VERSION 5.7 ;
  NOWIREEXTENSIONATPIN ON ;
  DIVIDERCHAR "/" ;
  BUSBITCHARS "[]" ;
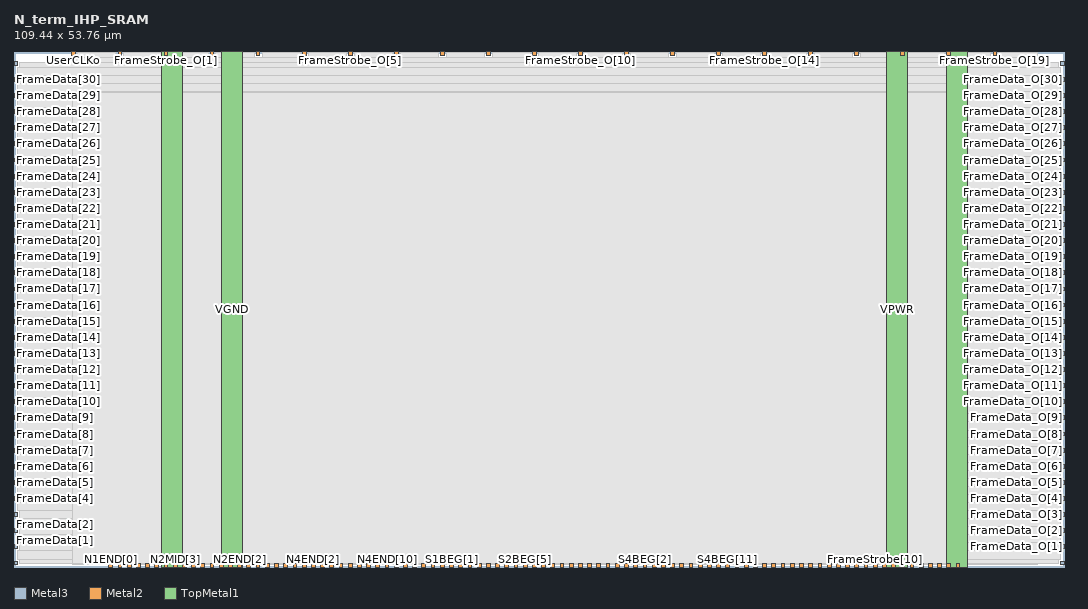
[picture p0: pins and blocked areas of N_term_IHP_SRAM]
MACRO N_term_IHP_SRAM
  CLASS BLOCK ;
  FOREIGN N_term_IHP_SRAM ;
  ORIGIN 0.000 0.000 ;
  SIZE 109.440 BY 53.760 ;
  PIN FrameData[0]
    DIRECTION INPUT ;
    USE SIGNAL ;
    ANTENNAGATEAREA 0.180700 ;
    PORT
      LAYER Metal3 ;
        RECT 0.000 0.220 0.400 0.620 ;
    END
  END FrameData[0]
  PIN FrameData[10]
    DIRECTION INPUT ;
    USE SIGNAL ;
    ANTENNAGATEAREA 0.180700 ;
    PORT
      LAYER Metal3 ;
        RECT 0.000 17.020 0.400 17.420 ;
    END
  END FrameData[10]
  PIN FrameData[11]
    DIRECTION INPUT ;
    USE SIGNAL ;
    ANTENNAGATEAREA 0.180700 ;
    PORT
      LAYER Metal3 ;
        RECT 0.000 18.700 0.400 19.100 ;
    END
  END FrameData[11]
  PIN FrameData[12]
    DIRECTION INPUT ;
    USE SIGNAL ;
    ANTENNAGATEAREA 0.180700 ;
    PORT
      LAYER Metal3 ;
        RECT 0.000 20.380 0.400 20.780 ;
    END
  END FrameData[12]
  PIN FrameData[13]
    DIRECTION INPUT ;
    USE SIGNAL ;
    ANTENNAGATEAREA 0.180700 ;
    PORT
      LAYER Metal3 ;
        RECT 0.000 22.060 0.400 22.460 ;
    END
  END FrameData[13]
  PIN FrameData[14]
    DIRECTION INPUT ;
    USE SIGNAL ;
    ANTENNAGATEAREA 0.180700 ;
    PORT
      LAYER Metal3 ;
        RECT 0.000 23.740 0.400 24.140 ;
    END
  END FrameData[14]
  PIN FrameData[15]
    DIRECTION INPUT ;
    USE SIGNAL ;
    ANTENNAGATEAREA 0.180700 ;
    PORT
      LAYER Metal3 ;
        RECT 0.000 25.420 0.400 25.820 ;
    END
  END FrameData[15]
  PIN FrameData[16]
    DIRECTION INPUT ;
    USE SIGNAL ;
    ANTENNAGATEAREA 0.180700 ;
    PORT
      LAYER Metal3 ;
        RECT 0.000 27.100 0.400 27.500 ;
    END
  END FrameData[16]
  PIN FrameData[17]
    DIRECTION INPUT ;
    USE SIGNAL ;
    ANTENNAGATEAREA 0.180700 ;
    PORT
      LAYER Metal3 ;
        RECT 0.000 28.780 0.400 29.180 ;
    END
  END FrameData[17]
  PIN FrameData[18]
    DIRECTION INPUT ;
    USE SIGNAL ;
    ANTENNAGATEAREA 0.180700 ;
    PORT
      LAYER Metal3 ;
        RECT 0.000 30.460 0.400 30.860 ;
    END
  END FrameData[18]
  PIN FrameData[19]
    DIRECTION INPUT ;
    USE SIGNAL ;
    ANTENNAGATEAREA 0.180700 ;
    PORT
      LAYER Metal3 ;
        RECT 0.000 32.140 0.400 32.540 ;
    END
  END FrameData[19]
  PIN FrameData[1]
    DIRECTION INPUT ;
    USE SIGNAL ;
    ANTENNAGATEAREA 0.180700 ;
    PORT
      LAYER Metal3 ;
        RECT 0.000 1.900 0.400 2.300 ;
    END
  END FrameData[1]
  PIN FrameData[20]
    DIRECTION INPUT ;
    USE SIGNAL ;
    ANTENNAGATEAREA 0.180700 ;
    PORT
      LAYER Metal3 ;
        RECT 0.000 33.820 0.400 34.220 ;
    END
  END FrameData[20]
  PIN FrameData[21]
    DIRECTION INPUT ;
    USE SIGNAL ;
    ANTENNAGATEAREA 0.180700 ;
    PORT
      LAYER Metal3 ;
        RECT 0.000 35.500 0.400 35.900 ;
    END
  END FrameData[21]
  PIN FrameData[22]
    DIRECTION INPUT ;
    USE SIGNAL ;
    ANTENNAGATEAREA 0.180700 ;
    PORT
      LAYER Metal3 ;
        RECT 0.000 37.180 0.400 37.580 ;
    END
  END FrameData[22]
  PIN FrameData[23]
    DIRECTION INPUT ;
    USE SIGNAL ;
    ANTENNAGATEAREA 0.180700 ;
    PORT
      LAYER Metal3 ;
        RECT 0.000 38.860 0.400 39.260 ;
    END
  END FrameData[23]
  PIN FrameData[24]
    DIRECTION INPUT ;
    USE SIGNAL ;
    ANTENNAGATEAREA 0.180700 ;
    PORT
      LAYER Metal3 ;
        RECT 0.000 40.540 0.400 40.940 ;
    END
  END FrameData[24]
  PIN FrameData[25]
    DIRECTION INPUT ;
    USE SIGNAL ;
    ANTENNAGATEAREA 0.180700 ;
    PORT
      LAYER Metal3 ;
        RECT 0.000 42.220 0.400 42.620 ;
    END
  END FrameData[25]
  PIN FrameData[26]
    DIRECTION INPUT ;
    USE SIGNAL ;
    ANTENNAGATEAREA 0.180700 ;
    PORT
      LAYER Metal3 ;
        RECT 0.000 43.900 0.400 44.300 ;
    END
  END FrameData[26]
  PIN FrameData[27]
    DIRECTION INPUT ;
    USE SIGNAL ;
    ANTENNAGATEAREA 0.180700 ;
    PORT
      LAYER Metal3 ;
        RECT 0.000 45.580 0.400 45.980 ;
    END
  END FrameData[27]
  PIN FrameData[28]
    DIRECTION INPUT ;
    USE SIGNAL ;
    ANTENNAGATEAREA 0.180700 ;
    PORT
      LAYER Metal3 ;
        RECT 0.000 47.260 0.400 47.660 ;
    END
  END FrameData[28]
  PIN FrameData[29]
    DIRECTION INPUT ;
    USE SIGNAL ;
    ANTENNAGATEAREA 0.180700 ;
    PORT
      LAYER Metal3 ;
        RECT 0.000 48.940 0.400 49.340 ;
    END
  END FrameData[29]
  PIN FrameData[2]
    DIRECTION INPUT ;
    USE SIGNAL ;
    ANTENNAGATEAREA 0.180700 ;
    PORT
      LAYER Metal3 ;
        RECT 0.000 3.580 0.400 3.980 ;
    END
  END FrameData[2]
  PIN FrameData[30]
    DIRECTION INPUT ;
    USE SIGNAL ;
    ANTENNAGATEAREA 0.180700 ;
    PORT
      LAYER Metal3 ;
        RECT 0.000 50.620 0.400 51.020 ;
    END
  END FrameData[30]
  PIN FrameData[31]
    DIRECTION INPUT ;
    USE SIGNAL ;
    ANTENNAGATEAREA 0.180700 ;
    PORT
      LAYER Metal3 ;
        RECT 0.000 52.300 0.400 52.700 ;
    END
  END FrameData[31]
  PIN FrameData[3]
    DIRECTION INPUT ;
    USE SIGNAL ;
    ANTENNAGATEAREA 0.180700 ;
    PORT
      LAYER Metal3 ;
        RECT 0.000 5.260 0.400 5.660 ;
    END
  END FrameData[3]
  PIN FrameData[4]
    DIRECTION INPUT ;
    USE SIGNAL ;
    ANTENNAGATEAREA 0.180700 ;
    PORT
      LAYER Metal3 ;
        RECT 0.000 6.940 0.400 7.340 ;
    END
  END FrameData[4]
  PIN FrameData[5]
    DIRECTION INPUT ;
    USE SIGNAL ;
    ANTENNAGATEAREA 0.180700 ;
    PORT
      LAYER Metal3 ;
        RECT 0.000 8.620 0.400 9.020 ;
    END
  END FrameData[5]
  PIN FrameData[6]
    DIRECTION INPUT ;
    USE SIGNAL ;
    ANTENNAGATEAREA 0.180700 ;
    PORT
      LAYER Metal3 ;
        RECT 0.000 10.300 0.400 10.700 ;
    END
  END FrameData[6]
  PIN FrameData[7]
    DIRECTION INPUT ;
    USE SIGNAL ;
    ANTENNAGATEAREA 0.180700 ;
    PORT
      LAYER Metal3 ;
        RECT 0.000 11.980 0.400 12.380 ;
    END
  END FrameData[7]
  PIN FrameData[8]
    DIRECTION INPUT ;
    USE SIGNAL ;
    ANTENNAGATEAREA 0.180700 ;
    PORT
      LAYER Metal3 ;
        RECT 0.000 13.660 0.400 14.060 ;
    END
  END FrameData[8]
  PIN FrameData[9]
    DIRECTION INPUT ;
    USE SIGNAL ;
    ANTENNAGATEAREA 0.180700 ;
    PORT
      LAYER Metal3 ;
        RECT 0.000 15.340 0.400 15.740 ;
    END
  END FrameData[9]
  PIN FrameData_O[0]
    DIRECTION OUTPUT ;
    USE SIGNAL ;
    ANTENNADIFFAREA 0.708600 ;
    PORT
      LAYER Metal3 ;
        RECT 109.040 0.220 109.440 0.620 ;
    END
  END FrameData_O[0]
  PIN FrameData_O[10]
    DIRECTION OUTPUT ;
    USE SIGNAL ;
    ANTENNADIFFAREA 0.708600 ;
    PORT
      LAYER Metal3 ;
        RECT 109.040 17.020 109.440 17.420 ;
    END
  END FrameData_O[10]
  PIN FrameData_O[11]
    DIRECTION OUTPUT ;
    USE SIGNAL ;
    ANTENNADIFFAREA 0.708600 ;
    PORT
      LAYER Metal3 ;
        RECT 109.040 18.700 109.440 19.100 ;
    END
  END FrameData_O[11]
  PIN FrameData_O[12]
    DIRECTION OUTPUT ;
    USE SIGNAL ;
    ANTENNADIFFAREA 0.708600 ;
    PORT
      LAYER Metal3 ;
        RECT 109.040 20.380 109.440 20.780 ;
    END
  END FrameData_O[12]
  PIN FrameData_O[13]
    DIRECTION OUTPUT ;
    USE SIGNAL ;
    ANTENNADIFFAREA 0.708600 ;
    PORT
      LAYER Metal3 ;
        RECT 109.040 22.060 109.440 22.460 ;
    END
  END FrameData_O[13]
  PIN FrameData_O[14]
    DIRECTION OUTPUT ;
    USE SIGNAL ;
    ANTENNADIFFAREA 0.708600 ;
    PORT
      LAYER Metal3 ;
        RECT 109.040 23.740 109.440 24.140 ;
    END
  END FrameData_O[14]
  PIN FrameData_O[15]
    DIRECTION OUTPUT ;
    USE SIGNAL ;
    ANTENNADIFFAREA 0.708600 ;
    PORT
      LAYER Metal3 ;
        RECT 109.040 25.420 109.440 25.820 ;
    END
  END FrameData_O[15]
  PIN FrameData_O[16]
    DIRECTION OUTPUT ;
    USE SIGNAL ;
    ANTENNADIFFAREA 0.708600 ;
    PORT
      LAYER Metal3 ;
        RECT 109.040 27.100 109.440 27.500 ;
    END
  END FrameData_O[16]
  PIN FrameData_O[17]
    DIRECTION OUTPUT ;
    USE SIGNAL ;
    ANTENNADIFFAREA 0.708600 ;
    PORT
      LAYER Metal3 ;
        RECT 109.040 28.780 109.440 29.180 ;
    END
  END FrameData_O[17]
  PIN FrameData_O[18]
    DIRECTION OUTPUT ;
    USE SIGNAL ;
    ANTENNADIFFAREA 0.708600 ;
    PORT
      LAYER Metal3 ;
        RECT 109.040 30.460 109.440 30.860 ;
    END
  END FrameData_O[18]
  PIN FrameData_O[19]
    DIRECTION OUTPUT ;
    USE SIGNAL ;
    ANTENNADIFFAREA 0.708600 ;
    PORT
      LAYER Metal3 ;
        RECT 109.040 32.140 109.440 32.540 ;
    END
  END FrameData_O[19]
  PIN FrameData_O[1]
    DIRECTION OUTPUT ;
    USE SIGNAL ;
    ANTENNADIFFAREA 0.708600 ;
    PORT
      LAYER Metal3 ;
        RECT 109.040 1.900 109.440 2.300 ;
    END
  END FrameData_O[1]
  PIN FrameData_O[20]
    DIRECTION OUTPUT ;
    USE SIGNAL ;
    ANTENNADIFFAREA 0.708600 ;
    PORT
      LAYER Metal3 ;
        RECT 109.040 33.820 109.440 34.220 ;
    END
  END FrameData_O[20]
  PIN FrameData_O[21]
    DIRECTION OUTPUT ;
    USE SIGNAL ;
    ANTENNADIFFAREA 0.708600 ;
    PORT
      LAYER Metal3 ;
        RECT 109.040 35.500 109.440 35.900 ;
    END
  END FrameData_O[21]
  PIN FrameData_O[22]
    DIRECTION OUTPUT ;
    USE SIGNAL ;
    ANTENNADIFFAREA 0.708600 ;
    PORT
      LAYER Metal3 ;
        RECT 109.040 37.180 109.440 37.580 ;
    END
  END FrameData_O[22]
  PIN FrameData_O[23]
    DIRECTION OUTPUT ;
    USE SIGNAL ;
    ANTENNADIFFAREA 0.708600 ;
    PORT
      LAYER Metal3 ;
        RECT 109.040 38.860 109.440 39.260 ;
    END
  END FrameData_O[23]
  PIN FrameData_O[24]
    DIRECTION OUTPUT ;
    USE SIGNAL ;
    ANTENNADIFFAREA 0.708600 ;
    PORT
      LAYER Metal3 ;
        RECT 109.040 40.540 109.440 40.940 ;
    END
  END FrameData_O[24]
  PIN FrameData_O[25]
    DIRECTION OUTPUT ;
    USE SIGNAL ;
    ANTENNADIFFAREA 0.708600 ;
    PORT
      LAYER Metal3 ;
        RECT 109.040 42.220 109.440 42.620 ;
    END
  END FrameData_O[25]
  PIN FrameData_O[26]
    DIRECTION OUTPUT ;
    USE SIGNAL ;
    ANTENNADIFFAREA 0.708600 ;
    PORT
      LAYER Metal3 ;
        RECT 109.040 43.900 109.440 44.300 ;
    END
  END FrameData_O[26]
  PIN FrameData_O[27]
    DIRECTION OUTPUT ;
    USE SIGNAL ;
    ANTENNADIFFAREA 0.708600 ;
    PORT
      LAYER Metal3 ;
        RECT 109.040 45.580 109.440 45.980 ;
    END
  END FrameData_O[27]
  PIN FrameData_O[28]
    DIRECTION OUTPUT ;
    USE SIGNAL ;
    ANTENNADIFFAREA 0.708600 ;
    PORT
      LAYER Metal3 ;
        RECT 109.040 47.260 109.440 47.660 ;
    END
  END FrameData_O[28]
  PIN FrameData_O[29]
    DIRECTION OUTPUT ;
    USE SIGNAL ;
    ANTENNADIFFAREA 0.708600 ;
    PORT
      LAYER Metal3 ;
        RECT 109.040 48.940 109.440 49.340 ;
    END
  END FrameData_O[29]
  PIN FrameData_O[2]
    DIRECTION OUTPUT ;
    USE SIGNAL ;
    ANTENNADIFFAREA 0.708600 ;
    PORT
      LAYER Metal3 ;
        RECT 109.040 3.580 109.440 3.980 ;
    END
  END FrameData_O[2]
  PIN FrameData_O[30]
    DIRECTION OUTPUT ;
    USE SIGNAL ;
    ANTENNADIFFAREA 0.708600 ;
    PORT
      LAYER Metal3 ;
        RECT 109.040 50.620 109.440 51.020 ;
    END
  END FrameData_O[30]
  PIN FrameData_O[31]
    DIRECTION OUTPUT ;
    USE SIGNAL ;
    ANTENNADIFFAREA 0.708600 ;
    PORT
      LAYER Metal3 ;
        RECT 109.040 52.300 109.440 52.700 ;
    END
  END FrameData_O[31]
  PIN FrameData_O[3]
    DIRECTION OUTPUT ;
    USE SIGNAL ;
    ANTENNADIFFAREA 0.708600 ;
    PORT
      LAYER Metal3 ;
        RECT 109.040 5.260 109.440 5.660 ;
    END
  END FrameData_O[3]
  PIN FrameData_O[4]
    DIRECTION OUTPUT ;
    USE SIGNAL ;
    ANTENNADIFFAREA 0.708600 ;
    PORT
      LAYER Metal3 ;
        RECT 109.040 6.940 109.440 7.340 ;
    END
  END FrameData_O[4]
  PIN FrameData_O[5]
    DIRECTION OUTPUT ;
    USE SIGNAL ;
    ANTENNADIFFAREA 0.708600 ;
    PORT
      LAYER Metal3 ;
        RECT 109.040 8.620 109.440 9.020 ;
    END
  END FrameData_O[5]
  PIN FrameData_O[6]
    DIRECTION OUTPUT ;
    USE SIGNAL ;
    ANTENNADIFFAREA 0.708600 ;
    PORT
      LAYER Metal3 ;
        RECT 109.040 10.300 109.440 10.700 ;
    END
  END FrameData_O[6]
  PIN FrameData_O[7]
    DIRECTION OUTPUT ;
    USE SIGNAL ;
    ANTENNADIFFAREA 0.708600 ;
    PORT
      LAYER Metal3 ;
        RECT 109.040 11.980 109.440 12.380 ;
    END
  END FrameData_O[7]
  PIN FrameData_O[8]
    DIRECTION OUTPUT ;
    USE SIGNAL ;
    ANTENNADIFFAREA 0.708600 ;
    PORT
      LAYER Metal3 ;
        RECT 109.040 13.660 109.440 14.060 ;
    END
  END FrameData_O[8]
  PIN FrameData_O[9]
    DIRECTION OUTPUT ;
    USE SIGNAL ;
    ANTENNADIFFAREA 0.708600 ;
    PORT
      LAYER Metal3 ;
        RECT 109.040 15.340 109.440 15.740 ;
    END
  END FrameData_O[9]
  PIN FrameStrobe[0]
    DIRECTION INPUT ;
    USE SIGNAL ;
    ANTENNAGATEAREA 0.180700 ;
    PORT
      LAYER Metal2 ;
        RECT 79.960 0.000 80.360 0.400 ;
    END
  END FrameStrobe[0]
  PIN FrameStrobe[10]
    DIRECTION INPUT ;
    USE SIGNAL ;
    ANTENNAGATEAREA 0.180700 ;
    PORT
      LAYER Metal2 ;
        RECT 89.560 0.000 89.960 0.400 ;
    END
  END FrameStrobe[10]
  PIN FrameStrobe[11]
    DIRECTION INPUT ;
    USE SIGNAL ;
    ANTENNAGATEAREA 0.180700 ;
    PORT
      LAYER Metal2 ;
        RECT 90.520 0.000 90.920 0.400 ;
    END
  END FrameStrobe[11]
  PIN FrameStrobe[12]
    DIRECTION INPUT ;
    USE SIGNAL ;
    ANTENNAGATEAREA 0.180700 ;
    PORT
      LAYER Metal2 ;
        RECT 91.480 0.000 91.880 0.400 ;
    END
  END FrameStrobe[12]
  PIN FrameStrobe[13]
    DIRECTION INPUT ;
    USE SIGNAL ;
    ANTENNAGATEAREA 0.180700 ;
    PORT
      LAYER Metal2 ;
        RECT 92.440 0.000 92.840 0.400 ;
    END
  END FrameStrobe[13]
  PIN FrameStrobe[14]
    DIRECTION INPUT ;
    USE SIGNAL ;
    ANTENNAGATEAREA 0.180700 ;
    PORT
      LAYER Metal2 ;
        RECT 93.400 0.000 93.800 0.400 ;
    END
  END FrameStrobe[14]
  PIN FrameStrobe[15]
    DIRECTION INPUT ;
    USE SIGNAL ;
    ANTENNAGATEAREA 0.180700 ;
    PORT
      LAYER Metal2 ;
        RECT 94.360 0.000 94.760 0.400 ;
    END
  END FrameStrobe[15]
  PIN FrameStrobe[16]
    DIRECTION INPUT ;
    USE SIGNAL ;
    ANTENNAGATEAREA 0.180700 ;
    PORT
      LAYER Metal2 ;
        RECT 95.320 0.000 95.720 0.400 ;
    END
  END FrameStrobe[16]
  PIN FrameStrobe[17]
    DIRECTION INPUT ;
    USE SIGNAL ;
    ANTENNAGATEAREA 0.180700 ;
    PORT
      LAYER Metal2 ;
        RECT 96.280 0.000 96.680 0.400 ;
    END
  END FrameStrobe[17]
  PIN FrameStrobe[18]
    DIRECTION INPUT ;
    USE SIGNAL ;
    ANTENNAGATEAREA 0.180700 ;
    PORT
      LAYER Metal2 ;
        RECT 97.240 0.000 97.640 0.400 ;
    END
  END FrameStrobe[18]
  PIN FrameStrobe[19]
    DIRECTION INPUT ;
    USE SIGNAL ;
    ANTENNAGATEAREA 0.180700 ;
    PORT
      LAYER Metal2 ;
        RECT 98.200 0.000 98.600 0.400 ;
    END
  END FrameStrobe[19]
  PIN FrameStrobe[1]
    DIRECTION INPUT ;
    USE SIGNAL ;
    ANTENNAGATEAREA 0.180700 ;
    PORT
      LAYER Metal2 ;
        RECT 80.920 0.000 81.320 0.400 ;
    END
  END FrameStrobe[1]
  PIN FrameStrobe[2]
    DIRECTION INPUT ;
    USE SIGNAL ;
    ANTENNAGATEAREA 0.180700 ;
    PORT
      LAYER Metal2 ;
        RECT 81.880 0.000 82.280 0.400 ;
    END
  END FrameStrobe[2]
  PIN FrameStrobe[3]
    DIRECTION INPUT ;
    USE SIGNAL ;
    ANTENNAGATEAREA 0.180700 ;
    PORT
      LAYER Metal2 ;
        RECT 82.840 0.000 83.240 0.400 ;
    END
  END FrameStrobe[3]
  PIN FrameStrobe[4]
    DIRECTION INPUT ;
    USE SIGNAL ;
    ANTENNAGATEAREA 0.180700 ;
    PORT
      LAYER Metal2 ;
        RECT 83.800 0.000 84.200 0.400 ;
    END
  END FrameStrobe[4]
  PIN FrameStrobe[5]
    DIRECTION INPUT ;
    USE SIGNAL ;
    ANTENNAGATEAREA 0.180700 ;
    PORT
      LAYER Metal2 ;
        RECT 84.760 0.000 85.160 0.400 ;
    END
  END FrameStrobe[5]
  PIN FrameStrobe[6]
    DIRECTION INPUT ;
    USE SIGNAL ;
    ANTENNAGATEAREA 0.180700 ;
    PORT
      LAYER Metal2 ;
        RECT 85.720 0.000 86.120 0.400 ;
    END
  END FrameStrobe[6]
  PIN FrameStrobe[7]
    DIRECTION INPUT ;
    USE SIGNAL ;
    ANTENNAGATEAREA 0.180700 ;
    PORT
      LAYER Metal2 ;
        RECT 86.680 0.000 87.080 0.400 ;
    END
  END FrameStrobe[7]
  PIN FrameStrobe[8]
    DIRECTION INPUT ;
    USE SIGNAL ;
    ANTENNAGATEAREA 0.180700 ;
    PORT
      LAYER Metal2 ;
        RECT 87.640 0.000 88.040 0.400 ;
    END
  END FrameStrobe[8]
  PIN FrameStrobe[9]
    DIRECTION INPUT ;
    USE SIGNAL ;
    ANTENNAGATEAREA 0.180700 ;
    PORT
      LAYER Metal2 ;
        RECT 88.600 0.000 89.000 0.400 ;
    END
  END FrameStrobe[9]
  PIN FrameStrobe_O[0]
    DIRECTION OUTPUT ;
    USE SIGNAL ;
    ANTENNADIFFAREA 0.708600 ;
    PORT
      LAYER Metal2 ;
        RECT 10.840 53.360 11.240 53.760 ;
    END
  END FrameStrobe_O[0]
  PIN FrameStrobe_O[10]
    DIRECTION OUTPUT ;
    USE SIGNAL ;
    ANTENNADIFFAREA 0.708600 ;
    PORT
      LAYER Metal2 ;
        RECT 58.840 53.360 59.240 53.760 ;
    END
  END FrameStrobe_O[10]
  PIN FrameStrobe_O[11]
    DIRECTION OUTPUT ;
    USE SIGNAL ;
    ANTENNADIFFAREA 0.708600 ;
    PORT
      LAYER Metal2 ;
        RECT 63.640 53.360 64.040 53.760 ;
    END
  END FrameStrobe_O[11]
  PIN FrameStrobe_O[12]
    DIRECTION OUTPUT ;
    USE SIGNAL ;
    ANTENNADIFFAREA 0.708600 ;
    PORT
      LAYER Metal2 ;
        RECT 68.440 53.360 68.840 53.760 ;
    END
  END FrameStrobe_O[12]
  PIN FrameStrobe_O[13]
    DIRECTION OUTPUT ;
    USE SIGNAL ;
    ANTENNADIFFAREA 0.708600 ;
    PORT
      LAYER Metal2 ;
        RECT 73.240 53.360 73.640 53.760 ;
    END
  END FrameStrobe_O[13]
  PIN FrameStrobe_O[14]
    DIRECTION OUTPUT ;
    USE SIGNAL ;
    ANTENNADIFFAREA 0.708600 ;
    PORT
      LAYER Metal2 ;
        RECT 78.040 53.360 78.440 53.760 ;
    END
  END FrameStrobe_O[14]
  PIN FrameStrobe_O[15]
    DIRECTION OUTPUT ;
    USE SIGNAL ;
    ANTENNADIFFAREA 0.708600 ;
    PORT
      LAYER Metal2 ;
        RECT 82.840 53.360 83.240 53.760 ;
    END
  END FrameStrobe_O[15]
  PIN FrameStrobe_O[16]
    DIRECTION OUTPUT ;
    USE SIGNAL ;
    ANTENNADIFFAREA 0.708600 ;
    PORT
      LAYER Metal2 ;
        RECT 87.640 53.360 88.040 53.760 ;
    END
  END FrameStrobe_O[16]
  PIN FrameStrobe_O[17]
    DIRECTION OUTPUT ;
    USE SIGNAL ;
    ANTENNADIFFAREA 0.708600 ;
    PORT
      LAYER Metal2 ;
        RECT 92.440 53.360 92.840 53.760 ;
    END
  END FrameStrobe_O[17]
  PIN FrameStrobe_O[18]
    DIRECTION OUTPUT ;
    USE SIGNAL ;
    ANTENNADIFFAREA 0.708600 ;
    PORT
      LAYER Metal2 ;
        RECT 97.240 53.360 97.640 53.760 ;
    END
  END FrameStrobe_O[18]
  PIN FrameStrobe_O[19]
    DIRECTION OUTPUT ;
    USE SIGNAL ;
    ANTENNADIFFAREA 0.708600 ;
    PORT
      LAYER Metal2 ;
        RECT 102.040 53.360 102.440 53.760 ;
    END
  END FrameStrobe_O[19]
  PIN FrameStrobe_O[1]
    DIRECTION OUTPUT ;
    USE SIGNAL ;
    ANTENNADIFFAREA 0.708600 ;
    PORT
      LAYER Metal2 ;
        RECT 15.640 53.360 16.040 53.760 ;
    END
  END FrameStrobe_O[1]
  PIN FrameStrobe_O[2]
    DIRECTION OUTPUT ;
    USE SIGNAL ;
    ANTENNADIFFAREA 0.708600 ;
    PORT
      LAYER Metal2 ;
        RECT 20.440 53.360 20.840 53.760 ;
    END
  END FrameStrobe_O[2]
  PIN FrameStrobe_O[3]
    DIRECTION OUTPUT ;
    USE SIGNAL ;
    ANTENNADIFFAREA 0.708600 ;
    PORT
      LAYER Metal2 ;
        RECT 25.240 53.360 25.640 53.760 ;
    END
  END FrameStrobe_O[3]
  PIN FrameStrobe_O[4]
    DIRECTION OUTPUT ;
    USE SIGNAL ;
    ANTENNADIFFAREA 0.708600 ;
    PORT
      LAYER Metal2 ;
        RECT 30.040 53.360 30.440 53.760 ;
    END
  END FrameStrobe_O[4]
  PIN FrameStrobe_O[5]
    DIRECTION OUTPUT ;
    USE SIGNAL ;
    ANTENNADIFFAREA 0.708600 ;
    PORT
      LAYER Metal2 ;
        RECT 34.840 53.360 35.240 53.760 ;
    END
  END FrameStrobe_O[5]
  PIN FrameStrobe_O[6]
    DIRECTION OUTPUT ;
    USE SIGNAL ;
    ANTENNADIFFAREA 0.708600 ;
    PORT
      LAYER Metal2 ;
        RECT 39.640 53.360 40.040 53.760 ;
    END
  END FrameStrobe_O[6]
  PIN FrameStrobe_O[7]
    DIRECTION OUTPUT ;
    USE SIGNAL ;
    ANTENNADIFFAREA 0.708600 ;
    PORT
      LAYER Metal2 ;
        RECT 44.440 53.360 44.840 53.760 ;
    END
  END FrameStrobe_O[7]
  PIN FrameStrobe_O[8]
    DIRECTION OUTPUT ;
    USE SIGNAL ;
    ANTENNADIFFAREA 0.708600 ;
    PORT
      LAYER Metal2 ;
        RECT 49.240 53.360 49.640 53.760 ;
    END
  END FrameStrobe_O[8]
  PIN FrameStrobe_O[9]
    DIRECTION OUTPUT ;
    USE SIGNAL ;
    ANTENNADIFFAREA 0.708600 ;
    PORT
      LAYER Metal2 ;
        RECT 54.040 53.360 54.440 53.760 ;
    END
  END FrameStrobe_O[9]
  PIN N1END[0]
    DIRECTION INPUT ;
    USE SIGNAL ;
    ANTENNAGATEAREA 0.180700 ;
    PORT
      LAYER Metal2 ;
        RECT 9.880 0.000 10.280 0.400 ;
    END
  END N1END[0]
  PIN N1END[1]
    DIRECTION INPUT ;
    USE SIGNAL ;
    ANTENNAGATEAREA 0.180700 ;
    PORT
      LAYER Metal2 ;
        RECT 10.840 0.000 11.240 0.400 ;
    END
  END N1END[1]
  PIN N1END[2]
    DIRECTION INPUT ;
    USE SIGNAL ;
    ANTENNAGATEAREA 0.180700 ;
    PORT
      LAYER Metal2 ;
        RECT 11.800 0.000 12.200 0.400 ;
    END
  END N1END[2]
  PIN N1END[3]
    DIRECTION INPUT ;
    USE SIGNAL ;
    ANTENNAGATEAREA 0.180700 ;
    PORT
      LAYER Metal2 ;
        RECT 12.760 0.000 13.160 0.400 ;
    END
  END N1END[3]
  PIN N2END[0]
    DIRECTION INPUT ;
    USE SIGNAL ;
    ANTENNAGATEAREA 0.180700 ;
    PORT
      LAYER Metal2 ;
        RECT 21.400 0.000 21.800 0.400 ;
    END
  END N2END[0]
  PIN N2END[1]
    DIRECTION INPUT ;
    USE SIGNAL ;
    ANTENNAGATEAREA 0.180700 ;
    PORT
      LAYER Metal2 ;
        RECT 22.360 0.000 22.760 0.400 ;
    END
  END N2END[1]
  PIN N2END[2]
    DIRECTION INPUT ;
    USE SIGNAL ;
    ANTENNAGATEAREA 0.180700 ;
    PORT
      LAYER Metal2 ;
        RECT 23.320 0.000 23.720 0.400 ;
    END
  END N2END[2]
  PIN N2END[3]
    DIRECTION INPUT ;
    USE SIGNAL ;
    ANTENNAGATEAREA 0.180700 ;
    PORT
      LAYER Metal2 ;
        RECT 24.280 0.000 24.680 0.400 ;
    END
  END N2END[3]
  PIN N2END[4]
    DIRECTION INPUT ;
    USE SIGNAL ;
    ANTENNAGATEAREA 0.180700 ;
    PORT
      LAYER Metal2 ;
        RECT 25.240 0.000 25.640 0.400 ;
    END
  END N2END[4]
  PIN N2END[5]
    DIRECTION INPUT ;
    USE SIGNAL ;
    ANTENNAGATEAREA 0.180700 ;
    PORT
      LAYER Metal2 ;
        RECT 26.200 0.000 26.600 0.400 ;
    END
  END N2END[5]
  PIN N2END[6]
    DIRECTION INPUT ;
    USE SIGNAL ;
    ANTENNAGATEAREA 0.180700 ;
    PORT
      LAYER Metal2 ;
        RECT 27.160 0.000 27.560 0.400 ;
    END
  END N2END[6]
  PIN N2END[7]
    DIRECTION INPUT ;
    USE SIGNAL ;
    ANTENNAGATEAREA 0.180700 ;
    PORT
      LAYER Metal2 ;
        RECT 28.120 0.000 28.520 0.400 ;
    END
  END N2END[7]
  PIN N2MID[0]
    DIRECTION INPUT ;
    USE SIGNAL ;
    ANTENNAGATEAREA 0.180700 ;
    PORT
      LAYER Metal2 ;
        RECT 13.720 0.000 14.120 0.400 ;
    END
  END N2MID[0]
  PIN N2MID[1]
    DIRECTION INPUT ;
    USE SIGNAL ;
    ANTENNAGATEAREA 0.180700 ;
    PORT
      LAYER Metal2 ;
        RECT 14.680 0.000 15.080 0.400 ;
    END
  END N2MID[1]
  PIN N2MID[2]
    DIRECTION INPUT ;
    USE SIGNAL ;
    ANTENNAGATEAREA 0.180700 ;
    PORT
      LAYER Metal2 ;
        RECT 15.640 0.000 16.040 0.400 ;
    END
  END N2MID[2]
  PIN N2MID[3]
    DIRECTION INPUT ;
    USE SIGNAL ;
    ANTENNAGATEAREA 0.180700 ;
    PORT
      LAYER Metal2 ;
        RECT 16.600 0.000 17.000 0.400 ;
    END
  END N2MID[3]
  PIN N2MID[4]
    DIRECTION INPUT ;
    USE SIGNAL ;
    ANTENNAGATEAREA 0.180700 ;
    PORT
      LAYER Metal2 ;
        RECT 17.560 0.000 17.960 0.400 ;
    END
  END N2MID[4]
  PIN N2MID[5]
    DIRECTION INPUT ;
    USE SIGNAL ;
    ANTENNAGATEAREA 0.180700 ;
    PORT
      LAYER Metal2 ;
        RECT 18.520 0.000 18.920 0.400 ;
    END
  END N2MID[5]
  PIN N2MID[6]
    DIRECTION INPUT ;
    USE SIGNAL ;
    ANTENNAGATEAREA 0.180700 ;
    PORT
      LAYER Metal2 ;
        RECT 19.480 0.000 19.880 0.400 ;
    END
  END N2MID[6]
  PIN N2MID[7]
    DIRECTION INPUT ;
    USE SIGNAL ;
    ANTENNAGATEAREA 0.180700 ;
    PORT
      LAYER Metal2 ;
        RECT 20.440 0.000 20.840 0.400 ;
    END
  END N2MID[7]
  PIN N4END[0]
    DIRECTION INPUT ;
    USE SIGNAL ;
    ANTENNAGATEAREA 0.180700 ;
    PORT
      LAYER Metal2 ;
        RECT 29.080 0.000 29.480 0.400 ;
    END
  END N4END[0]
  PIN N4END[10]
    DIRECTION INPUT ;
    USE SIGNAL ;
    ANTENNAGATEAREA 0.180700 ;
    PORT
      LAYER Metal2 ;
        RECT 38.680 0.000 39.080 0.400 ;
    END
  END N4END[10]
  PIN N4END[11]
    DIRECTION INPUT ;
    USE SIGNAL ;
    ANTENNAGATEAREA 0.180700 ;
    PORT
      LAYER Metal2 ;
        RECT 39.640 0.000 40.040 0.400 ;
    END
  END N4END[11]
  PIN N4END[12]
    DIRECTION INPUT ;
    USE SIGNAL ;
    ANTENNAGATEAREA 0.180700 ;
    PORT
      LAYER Metal2 ;
        RECT 40.600 0.000 41.000 0.400 ;
    END
  END N4END[12]
  PIN N4END[13]
    DIRECTION INPUT ;
    USE SIGNAL ;
    ANTENNAGATEAREA 0.180700 ;
    PORT
      LAYER Metal2 ;
        RECT 41.560 0.000 41.960 0.400 ;
    END
  END N4END[13]
  PIN N4END[14]
    DIRECTION INPUT ;
    USE SIGNAL ;
    ANTENNAGATEAREA 0.180700 ;
    PORT
      LAYER Metal2 ;
        RECT 42.520 0.000 42.920 0.400 ;
    END
  END N4END[14]
  PIN N4END[15]
    DIRECTION INPUT ;
    USE SIGNAL ;
    ANTENNAGATEAREA 0.180700 ;
    PORT
      LAYER Metal2 ;
        RECT 43.480 0.000 43.880 0.400 ;
    END
  END N4END[15]
  PIN N4END[1]
    DIRECTION INPUT ;
    USE SIGNAL ;
    ANTENNAGATEAREA 0.180700 ;
    PORT
      LAYER Metal2 ;
        RECT 30.040 0.000 30.440 0.400 ;
    END
  END N4END[1]
  PIN N4END[2]
    DIRECTION INPUT ;
    USE SIGNAL ;
    ANTENNAGATEAREA 0.180700 ;
    PORT
      LAYER Metal2 ;
        RECT 31.000 0.000 31.400 0.400 ;
    END
  END N4END[2]
  PIN N4END[3]
    DIRECTION INPUT ;
    USE SIGNAL ;
    ANTENNAGATEAREA 0.180700 ;
    PORT
      LAYER Metal2 ;
        RECT 31.960 0.000 32.360 0.400 ;
    END
  END N4END[3]
  PIN N4END[4]
    DIRECTION INPUT ;
    USE SIGNAL ;
    ANTENNAGATEAREA 0.180700 ;
    PORT
      LAYER Metal2 ;
        RECT 32.920 0.000 33.320 0.400 ;
    END
  END N4END[4]
  PIN N4END[5]
    DIRECTION INPUT ;
    USE SIGNAL ;
    ANTENNAGATEAREA 0.180700 ;
    PORT
      LAYER Metal2 ;
        RECT 33.880 0.000 34.280 0.400 ;
    END
  END N4END[5]
  PIN N4END[6]
    DIRECTION INPUT ;
    USE SIGNAL ;
    ANTENNAGATEAREA 0.180700 ;
    PORT
      LAYER Metal2 ;
        RECT 34.840 0.000 35.240 0.400 ;
    END
  END N4END[6]
  PIN N4END[7]
    DIRECTION INPUT ;
    USE SIGNAL ;
    ANTENNAGATEAREA 0.180700 ;
    PORT
      LAYER Metal2 ;
        RECT 35.800 0.000 36.200 0.400 ;
    END
  END N4END[7]
  PIN N4END[8]
    DIRECTION INPUT ;
    USE SIGNAL ;
    ANTENNAGATEAREA 0.180700 ;
    PORT
      LAYER Metal2 ;
        RECT 36.760 0.000 37.160 0.400 ;
    END
  END N4END[8]
  PIN N4END[9]
    DIRECTION INPUT ;
    USE SIGNAL ;
    ANTENNAGATEAREA 0.180700 ;
    PORT
      LAYER Metal2 ;
        RECT 37.720 0.000 38.120 0.400 ;
    END
  END N4END[9]
  PIN S1BEG[0]
    DIRECTION OUTPUT ;
    USE SIGNAL ;
    ANTENNADIFFAREA 0.708600 ;
    PORT
      LAYER Metal2 ;
        RECT 44.440 0.000 44.840 0.400 ;
    END
  END S1BEG[0]
  PIN S1BEG[1]
    DIRECTION OUTPUT ;
    USE SIGNAL ;
    ANTENNADIFFAREA 0.708600 ;
    PORT
      LAYER Metal2 ;
        RECT 45.400 0.000 45.800 0.400 ;
    END
  END S1BEG[1]
  PIN S1BEG[2]
    DIRECTION OUTPUT ;
    USE SIGNAL ;
    ANTENNADIFFAREA 0.708600 ;
    PORT
      LAYER Metal2 ;
        RECT 46.360 0.000 46.760 0.400 ;
    END
  END S1BEG[2]
  PIN S1BEG[3]
    DIRECTION OUTPUT ;
    USE SIGNAL ;
    ANTENNADIFFAREA 0.708600 ;
    PORT
      LAYER Metal2 ;
        RECT 47.320 0.000 47.720 0.400 ;
    END
  END S1BEG[3]
  PIN S2BEG[0]
    DIRECTION OUTPUT ;
    USE SIGNAL ;
    ANTENNADIFFAREA 0.708600 ;
    PORT
      LAYER Metal2 ;
        RECT 48.280 0.000 48.680 0.400 ;
    END
  END S2BEG[0]
  PIN S2BEG[1]
    DIRECTION OUTPUT ;
    USE SIGNAL ;
    ANTENNADIFFAREA 0.708600 ;
    PORT
      LAYER Metal2 ;
        RECT 49.240 0.000 49.640 0.400 ;
    END
  END S2BEG[1]
  PIN S2BEG[2]
    DIRECTION OUTPUT ;
    USE SIGNAL ;
    ANTENNADIFFAREA 0.708600 ;
    PORT
      LAYER Metal2 ;
        RECT 50.200 0.000 50.600 0.400 ;
    END
  END S2BEG[2]
  PIN S2BEG[3]
    DIRECTION OUTPUT ;
    USE SIGNAL ;
    ANTENNADIFFAREA 0.708600 ;
    PORT
      LAYER Metal2 ;
        RECT 51.160 0.000 51.560 0.400 ;
    END
  END S2BEG[3]
  PIN S2BEG[4]
    DIRECTION OUTPUT ;
    USE SIGNAL ;
    ANTENNADIFFAREA 0.708600 ;
    PORT
      LAYER Metal2 ;
        RECT 52.120 0.000 52.520 0.400 ;
    END
  END S2BEG[4]
  PIN S2BEG[5]
    DIRECTION OUTPUT ;
    USE SIGNAL ;
    ANTENNADIFFAREA 0.708600 ;
    PORT
      LAYER Metal2 ;
        RECT 53.080 0.000 53.480 0.400 ;
    END
  END S2BEG[5]
  PIN S2BEG[6]
    DIRECTION OUTPUT ;
    USE SIGNAL ;
    ANTENNADIFFAREA 0.708600 ;
    PORT
      LAYER Metal2 ;
        RECT 54.040 0.000 54.440 0.400 ;
    END
  END S2BEG[6]
  PIN S2BEG[7]
    DIRECTION OUTPUT ;
    USE SIGNAL ;
    ANTENNADIFFAREA 0.708600 ;
    PORT
      LAYER Metal2 ;
        RECT 55.000 0.000 55.400 0.400 ;
    END
  END S2BEG[7]
  PIN S2BEGb[0]
    DIRECTION OUTPUT ;
    USE SIGNAL ;
    ANTENNADIFFAREA 0.708600 ;
    PORT
      LAYER Metal2 ;
        RECT 55.960 0.000 56.360 0.400 ;
    END
  END S2BEGb[0]
  PIN S2BEGb[1]
    DIRECTION OUTPUT ;
    USE SIGNAL ;
    ANTENNADIFFAREA 0.708600 ;
    PORT
      LAYER Metal2 ;
        RECT 56.920 0.000 57.320 0.400 ;
    END
  END S2BEGb[1]
  PIN S2BEGb[2]
    DIRECTION OUTPUT ;
    USE SIGNAL ;
    ANTENNADIFFAREA 0.708600 ;
    PORT
      LAYER Metal2 ;
        RECT 57.880 0.000 58.280 0.400 ;
    END
  END S2BEGb[2]
  PIN S2BEGb[3]
    DIRECTION OUTPUT ;
    USE SIGNAL ;
    ANTENNADIFFAREA 0.708600 ;
    PORT
      LAYER Metal2 ;
        RECT 58.840 0.000 59.240 0.400 ;
    END
  END S2BEGb[3]
  PIN S2BEGb[4]
    DIRECTION OUTPUT ;
    USE SIGNAL ;
    ANTENNADIFFAREA 0.708600 ;
    PORT
      LAYER Metal2 ;
        RECT 59.800 0.000 60.200 0.400 ;
    END
  END S2BEGb[4]
  PIN S2BEGb[5]
    DIRECTION OUTPUT ;
    USE SIGNAL ;
    ANTENNADIFFAREA 0.708600 ;
    PORT
      LAYER Metal2 ;
        RECT 60.760 0.000 61.160 0.400 ;
    END
  END S2BEGb[5]
  PIN S2BEGb[6]
    DIRECTION OUTPUT ;
    USE SIGNAL ;
    ANTENNADIFFAREA 0.708600 ;
    PORT
      LAYER Metal2 ;
        RECT 61.720 0.000 62.120 0.400 ;
    END
  END S2BEGb[6]
  PIN S2BEGb[7]
    DIRECTION OUTPUT ;
    USE SIGNAL ;
    ANTENNADIFFAREA 0.708600 ;
    PORT
      LAYER Metal2 ;
        RECT 62.680 0.000 63.080 0.400 ;
    END
  END S2BEGb[7]
  PIN S4BEG[0]
    DIRECTION OUTPUT ;
    USE SIGNAL ;
    ANTENNADIFFAREA 0.708600 ;
    PORT
      LAYER Metal2 ;
        RECT 63.640 0.000 64.040 0.400 ;
    END
  END S4BEG[0]
  PIN S4BEG[10]
    DIRECTION OUTPUT ;
    USE SIGNAL ;
    ANTENNADIFFAREA 0.708600 ;
    PORT
      LAYER Metal2 ;
        RECT 73.240 0.000 73.640 0.400 ;
    END
  END S4BEG[10]
  PIN S4BEG[11]
    DIRECTION OUTPUT ;
    USE SIGNAL ;
    ANTENNADIFFAREA 0.708600 ;
    PORT
      LAYER Metal2 ;
        RECT 74.200 0.000 74.600 0.400 ;
    END
  END S4BEG[11]
  PIN S4BEG[12]
    DIRECTION OUTPUT ;
    USE SIGNAL ;
    ANTENNADIFFAREA 0.708600 ;
    PORT
      LAYER Metal2 ;
        RECT 75.160 0.000 75.560 0.400 ;
    END
  END S4BEG[12]
  PIN S4BEG[13]
    DIRECTION OUTPUT ;
    USE SIGNAL ;
    ANTENNADIFFAREA 0.708600 ;
    PORT
      LAYER Metal2 ;
        RECT 76.120 0.000 76.520 0.400 ;
    END
  END S4BEG[13]
  PIN S4BEG[14]
    DIRECTION OUTPUT ;
    USE SIGNAL ;
    ANTENNADIFFAREA 0.708600 ;
    PORT
      LAYER Metal2 ;
        RECT 77.080 0.000 77.480 0.400 ;
    END
  END S4BEG[14]
  PIN S4BEG[15]
    DIRECTION OUTPUT ;
    USE SIGNAL ;
    ANTENNADIFFAREA 0.708600 ;
    PORT
      LAYER Metal2 ;
        RECT 78.040 0.000 78.440 0.400 ;
    END
  END S4BEG[15]
  PIN S4BEG[1]
    DIRECTION OUTPUT ;
    USE SIGNAL ;
    ANTENNADIFFAREA 0.708600 ;
    PORT
      LAYER Metal2 ;
        RECT 64.600 0.000 65.000 0.400 ;
    END
  END S4BEG[1]
  PIN S4BEG[2]
    DIRECTION OUTPUT ;
    USE SIGNAL ;
    ANTENNADIFFAREA 0.708600 ;
    PORT
      LAYER Metal2 ;
        RECT 65.560 0.000 65.960 0.400 ;
    END
  END S4BEG[2]
  PIN S4BEG[3]
    DIRECTION OUTPUT ;
    USE SIGNAL ;
    ANTENNADIFFAREA 0.708600 ;
    PORT
      LAYER Metal2 ;
        RECT 66.520 0.000 66.920 0.400 ;
    END
  END S4BEG[3]
  PIN S4BEG[4]
    DIRECTION OUTPUT ;
    USE SIGNAL ;
    ANTENNADIFFAREA 0.708600 ;
    PORT
      LAYER Metal2 ;
        RECT 67.480 0.000 67.880 0.400 ;
    END
  END S4BEG[4]
  PIN S4BEG[5]
    DIRECTION OUTPUT ;
    USE SIGNAL ;
    ANTENNADIFFAREA 0.708600 ;
    PORT
      LAYER Metal2 ;
        RECT 68.440 0.000 68.840 0.400 ;
    END
  END S4BEG[5]
  PIN S4BEG[6]
    DIRECTION OUTPUT ;
    USE SIGNAL ;
    ANTENNADIFFAREA 0.708600 ;
    PORT
      LAYER Metal2 ;
        RECT 69.400 0.000 69.800 0.400 ;
    END
  END S4BEG[6]
  PIN S4BEG[7]
    DIRECTION OUTPUT ;
    USE SIGNAL ;
    ANTENNADIFFAREA 0.708600 ;
    PORT
      LAYER Metal2 ;
        RECT 70.360 0.000 70.760 0.400 ;
    END
  END S4BEG[7]
  PIN S4BEG[8]
    DIRECTION OUTPUT ;
    USE SIGNAL ;
    ANTENNADIFFAREA 0.708600 ;
    PORT
      LAYER Metal2 ;
        RECT 71.320 0.000 71.720 0.400 ;
    END
  END S4BEG[8]
  PIN S4BEG[9]
    DIRECTION OUTPUT ;
    USE SIGNAL ;
    ANTENNADIFFAREA 0.708600 ;
    PORT
      LAYER Metal2 ;
        RECT 72.280 0.000 72.680 0.400 ;
    END
  END S4BEG[9]
  PIN UserCLK
    DIRECTION INPUT ;
    USE SIGNAL ;
    ANTENNAGATEAREA 0.180700 ;
    PORT
      LAYER Metal2 ;
        RECT 79.000 0.000 79.400 0.400 ;
    END
  END UserCLK
  PIN UserCLKo
    DIRECTION OUTPUT ;
    USE SIGNAL ;
    ANTENNADIFFAREA 0.708600 ;
    PORT
      LAYER Metal2 ;
        RECT 6.040 53.360 6.440 53.760 ;
    END
  END UserCLKo
  PIN VGND
    DIRECTION INOUT ;
    USE GROUND ;
    PORT
      LAYER TopMetal1 ;
        RECT 21.580 0.000 23.780 53.760 ;
    END
    PORT
      LAYER TopMetal1 ;
        RECT 97.180 0.000 99.380 53.760 ;
    END
  END VGND
  PIN VPWR
    DIRECTION INOUT ;
    USE POWER ;
    PORT
      LAYER TopMetal1 ;
        RECT 15.380 0.000 17.580 53.760 ;
    END
    PORT
      LAYER TopMetal1 ;
        RECT 90.980 0.000 93.180 53.760 ;
    END
  END VPWR
  OBS
      LAYER GatPoly ;
        RECT 2.880 3.630 106.560 49.290 ;
      LAYER Metal1 ;
        RECT 2.880 3.560 106.560 49.360 ;
      LAYER Metal2 ;
        RECT 6.650 53.150 10.630 53.660 ;
        RECT 11.450 53.150 15.430 53.660 ;
        RECT 16.250 53.150 20.230 53.660 ;
        RECT 21.050 53.150 25.030 53.660 ;
        RECT 25.850 53.150 29.830 53.660 ;
        RECT 30.650 53.150 34.630 53.660 ;
        RECT 35.450 53.150 39.430 53.660 ;
        RECT 40.250 53.150 44.230 53.660 ;
        RECT 45.050 53.150 49.030 53.660 ;
        RECT 49.850 53.150 53.830 53.660 ;
        RECT 54.650 53.150 58.630 53.660 ;
        RECT 59.450 53.150 63.430 53.660 ;
        RECT 64.250 53.150 68.230 53.660 ;
        RECT 69.050 53.150 73.030 53.660 ;
        RECT 73.850 53.150 77.830 53.660 ;
        RECT 78.650 53.150 82.630 53.660 ;
        RECT 83.450 53.150 87.430 53.660 ;
        RECT 88.250 53.150 92.230 53.660 ;
        RECT 93.050 53.150 97.030 53.660 ;
        RECT 97.850 53.150 101.830 53.660 ;
        RECT 102.650 53.150 106.665 53.660 ;
        RECT 6.140 0.610 106.665 53.150 ;
        RECT 6.140 0.275 9.670 0.610 ;
        RECT 10.490 0.275 10.630 0.610 ;
        RECT 11.450 0.275 11.590 0.610 ;
        RECT 12.410 0.275 12.550 0.610 ;
        RECT 13.370 0.275 13.510 0.610 ;
        RECT 14.330 0.275 14.470 0.610 ;
        RECT 15.290 0.275 15.430 0.610 ;
        RECT 16.250 0.275 16.390 0.610 ;
        RECT 17.210 0.275 17.350 0.610 ;
        RECT 18.170 0.275 18.310 0.610 ;
        RECT 19.130 0.275 19.270 0.610 ;
        RECT 20.090 0.275 20.230 0.610 ;
        RECT 21.050 0.275 21.190 0.610 ;
        RECT 22.010 0.275 22.150 0.610 ;
        RECT 22.970 0.275 23.110 0.610 ;
        RECT 23.930 0.275 24.070 0.610 ;
        RECT 24.890 0.275 25.030 0.610 ;
        RECT 25.850 0.275 25.990 0.610 ;
        RECT 26.810 0.275 26.950 0.610 ;
        RECT 27.770 0.275 27.910 0.610 ;
        RECT 28.730 0.275 28.870 0.610 ;
        RECT 29.690 0.275 29.830 0.610 ;
        RECT 30.650 0.275 30.790 0.610 ;
        RECT 31.610 0.275 31.750 0.610 ;
        RECT 32.570 0.275 32.710 0.610 ;
        RECT 33.530 0.275 33.670 0.610 ;
        RECT 34.490 0.275 34.630 0.610 ;
        RECT 35.450 0.275 35.590 0.610 ;
        RECT 36.410 0.275 36.550 0.610 ;
        RECT 37.370 0.275 37.510 0.610 ;
        RECT 38.330 0.275 38.470 0.610 ;
        RECT 39.290 0.275 39.430 0.610 ;
        RECT 40.250 0.275 40.390 0.610 ;
        RECT 41.210 0.275 41.350 0.610 ;
        RECT 42.170 0.275 42.310 0.610 ;
        RECT 43.130 0.275 43.270 0.610 ;
        RECT 44.090 0.275 44.230 0.610 ;
        RECT 45.050 0.275 45.190 0.610 ;
        RECT 46.010 0.275 46.150 0.610 ;
        RECT 46.970 0.275 47.110 0.610 ;
        RECT 47.930 0.275 48.070 0.610 ;
        RECT 48.890 0.275 49.030 0.610 ;
        RECT 49.850 0.275 49.990 0.610 ;
        RECT 50.810 0.275 50.950 0.610 ;
        RECT 51.770 0.275 51.910 0.610 ;
        RECT 52.730 0.275 52.870 0.610 ;
        RECT 53.690 0.275 53.830 0.610 ;
        RECT 54.650 0.275 54.790 0.610 ;
        RECT 55.610 0.275 55.750 0.610 ;
        RECT 56.570 0.275 56.710 0.610 ;
        RECT 57.530 0.275 57.670 0.610 ;
        RECT 58.490 0.275 58.630 0.610 ;
        RECT 59.450 0.275 59.590 0.610 ;
        RECT 60.410 0.275 60.550 0.610 ;
        RECT 61.370 0.275 61.510 0.610 ;
        RECT 62.330 0.275 62.470 0.610 ;
        RECT 63.290 0.275 63.430 0.610 ;
        RECT 64.250 0.275 64.390 0.610 ;
        RECT 65.210 0.275 65.350 0.610 ;
        RECT 66.170 0.275 66.310 0.610 ;
        RECT 67.130 0.275 67.270 0.610 ;
        RECT 68.090 0.275 68.230 0.610 ;
        RECT 69.050 0.275 69.190 0.610 ;
        RECT 70.010 0.275 70.150 0.610 ;
        RECT 70.970 0.275 71.110 0.610 ;
        RECT 71.930 0.275 72.070 0.610 ;
        RECT 72.890 0.275 73.030 0.610 ;
        RECT 73.850 0.275 73.990 0.610 ;
        RECT 74.810 0.275 74.950 0.610 ;
        RECT 75.770 0.275 75.910 0.610 ;
        RECT 76.730 0.275 76.870 0.610 ;
        RECT 77.690 0.275 77.830 0.610 ;
        RECT 78.650 0.275 78.790 0.610 ;
        RECT 79.610 0.275 79.750 0.610 ;
        RECT 80.570 0.275 80.710 0.610 ;
        RECT 81.530 0.275 81.670 0.610 ;
        RECT 82.490 0.275 82.630 0.610 ;
        RECT 83.450 0.275 83.590 0.610 ;
        RECT 84.410 0.275 84.550 0.610 ;
        RECT 85.370 0.275 85.510 0.610 ;
        RECT 86.330 0.275 86.470 0.610 ;
        RECT 87.290 0.275 87.430 0.610 ;
        RECT 88.250 0.275 88.390 0.610 ;
        RECT 89.210 0.275 89.350 0.610 ;
        RECT 90.170 0.275 90.310 0.610 ;
        RECT 91.130 0.275 91.270 0.610 ;
        RECT 92.090 0.275 92.230 0.610 ;
        RECT 93.050 0.275 93.190 0.610 ;
        RECT 94.010 0.275 94.150 0.610 ;
        RECT 94.970 0.275 95.110 0.610 ;
        RECT 95.930 0.275 96.070 0.610 ;
        RECT 96.890 0.275 97.030 0.610 ;
        RECT 97.850 0.275 97.990 0.610 ;
        RECT 98.810 0.275 106.665 0.610 ;
      LAYER Metal3 ;
        RECT 0.610 52.090 108.830 52.600 ;
        RECT 0.400 51.230 109.040 52.090 ;
        RECT 0.610 50.410 108.830 51.230 ;
        RECT 0.400 49.550 109.040 50.410 ;
        RECT 0.610 48.730 108.830 49.550 ;
        RECT 0.400 47.870 109.040 48.730 ;
        RECT 0.610 47.050 108.830 47.870 ;
        RECT 0.400 46.190 109.040 47.050 ;
        RECT 0.610 45.370 108.830 46.190 ;
        RECT 0.400 44.510 109.040 45.370 ;
        RECT 0.610 43.690 108.830 44.510 ;
        RECT 0.400 42.830 109.040 43.690 ;
        RECT 0.610 42.010 108.830 42.830 ;
        RECT 0.400 41.150 109.040 42.010 ;
        RECT 0.610 40.330 108.830 41.150 ;
        RECT 0.400 39.470 109.040 40.330 ;
        RECT 0.610 38.650 108.830 39.470 ;
        RECT 0.400 37.790 109.040 38.650 ;
        RECT 0.610 36.970 108.830 37.790 ;
        RECT 0.400 36.110 109.040 36.970 ;
        RECT 0.610 35.290 108.830 36.110 ;
        RECT 0.400 34.430 109.040 35.290 ;
        RECT 0.610 33.610 108.830 34.430 ;
        RECT 0.400 32.750 109.040 33.610 ;
        RECT 0.610 31.930 108.830 32.750 ;
        RECT 0.400 31.070 109.040 31.930 ;
        RECT 0.610 30.250 108.830 31.070 ;
        RECT 0.400 29.390 109.040 30.250 ;
        RECT 0.610 28.570 108.830 29.390 ;
        RECT 0.400 27.710 109.040 28.570 ;
        RECT 0.610 26.890 108.830 27.710 ;
        RECT 0.400 26.030 109.040 26.890 ;
        RECT 0.610 25.210 108.830 26.030 ;
        RECT 0.400 24.350 109.040 25.210 ;
        RECT 0.610 23.530 108.830 24.350 ;
        RECT 0.400 22.670 109.040 23.530 ;
        RECT 0.610 21.850 108.830 22.670 ;
        RECT 0.400 20.990 109.040 21.850 ;
        RECT 0.610 20.170 108.830 20.990 ;
        RECT 0.400 19.310 109.040 20.170 ;
        RECT 0.610 18.490 108.830 19.310 ;
        RECT 0.400 17.630 109.040 18.490 ;
        RECT 0.610 16.810 108.830 17.630 ;
        RECT 0.400 15.950 109.040 16.810 ;
        RECT 0.610 15.130 108.830 15.950 ;
        RECT 0.400 14.270 109.040 15.130 ;
        RECT 0.610 13.450 108.830 14.270 ;
        RECT 0.400 12.590 109.040 13.450 ;
        RECT 0.610 11.770 108.830 12.590 ;
        RECT 0.400 10.910 109.040 11.770 ;
        RECT 0.610 10.090 108.830 10.910 ;
        RECT 0.400 9.230 109.040 10.090 ;
        RECT 0.610 8.410 108.830 9.230 ;
        RECT 0.400 7.550 109.040 8.410 ;
        RECT 0.610 6.730 108.830 7.550 ;
        RECT 0.400 5.870 109.040 6.730 ;
        RECT 0.610 5.050 108.830 5.870 ;
        RECT 0.400 4.190 109.040 5.050 ;
        RECT 0.610 3.370 108.830 4.190 ;
        RECT 0.400 2.510 109.040 3.370 ;
        RECT 0.610 1.690 108.830 2.510 ;
        RECT 0.400 0.830 109.040 1.690 ;
        RECT 0.610 0.320 108.830 0.830 ;
      LAYER Metal4 ;
        RECT 6.135 0.270 99.200 49.285 ;
      LAYER Metal5 ;
        RECT 6.095 0.320 99.245 49.450 ;
  END
END N_term_IHP_SRAM
END LIBRARY

